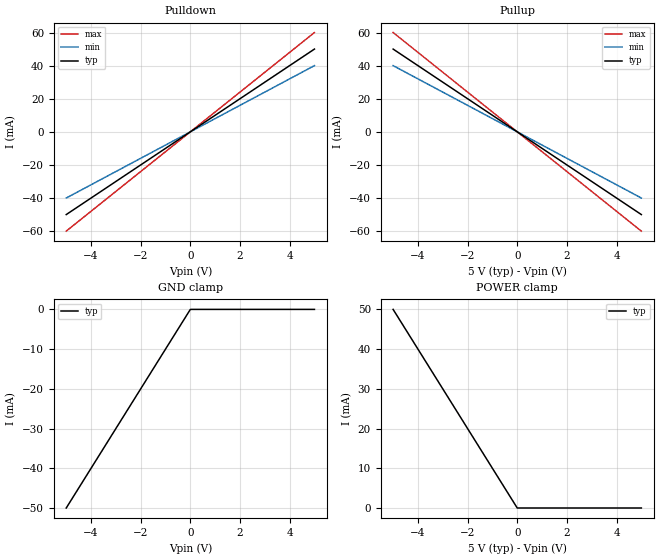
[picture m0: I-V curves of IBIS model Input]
[IBIS Ver]   1.1  |Let's test a comment
[Comment char]  #_char
[File name]   ibis_v1_1.ibs
[File Rev]   1.0  #Let's test a comment
[Date]   26/08/2021
[Source]   This is the
   source for the files
[Notes]   We can have some
   Notes
[Disclaimer]
 * This program source code file is part of KiCad, a free EDA CAD application.
 * Copyright (C) 2017-2021 KiCad Developers, see AUTHORS.txt for contributors.
 * This program is free software; you can redistribute it and/or
 * modify it under the terms of the GNU General Public License
 * as published by the Free Software Foundation; either version 2
 * of the License, or (at your option) any later version.
 * This program is distributed in the hope that it will be useful,
 * but WITHOUT ANY WARRANTY; without even the implied warranty of
 * MERCHANTABILITY or FITNESS FOR A PARTICULAR PURPOSE.  See the
 * GNU General Public License for more details.
 * You should have received a copy of the GNU General Public License
 * along with this program; if not, you may find one here:
 * http://www.gnu.org/licenses/old-licenses/gpl-2.0.html
 * or you may search the http://www.gnu.org website for the version 2 license,
 * or you may write to the Free Software Foundation, Inc.,
 * 51 Franklin Street, Fifth Floor, Boston, MA  02110-1301, USA
[Component]   Virtual
[Manufacturer]  KiCad
[Package]
R_pkg   1m   0.8m   NA
L_pkg   1m   NA   NA
C_pkg   1m   NA   NA
[Pin]   signal_name   model_name   R_pin   L_pin   C_pin
  1   VCC   POWER   1m   0.8m   NA
  2   GND   GND   1m   NA   2m
  3   X   Input   1m   NA   NA
  4   Y   Output   1m   0.8m   2m
# Models and submodels in the file (1): Input (Input)
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[Model]   Input
Model_type   Input
Polarity   Non-Inverting
Enable   Active-High
Vinl = 0.8V
Vinh = 2.0V
C_comp   10.0pF   8.0pF   15.0pF
[Voltage range]   5.0V   4.5V   5.5V
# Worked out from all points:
#   slope of the pulldown table from 0 to 0.75 V, typ, clamps not added: 100 ohm
#   slope of the pullup table from 0 to 0.75 V, typ, clamps not added: 100 ohm
[Pulldown]
#  Voltage   I(typ)   I(min)   I(max)
-5V       -50mA      -40mA      -60mA
0V        0A         0A         0A
5V        50mA       40mA       60mA
[Pullup]
#  Voltage   I(typ)   I(min)   I(max)
-5V       50mA       40mA       60mA
0V        0A         0A         0A
5V        -50mA      -40mA      -60mA
[GND_clamp]
#  Voltage   I(typ)   I(min)   I(max)
-5V       -50mA      NA         NA
0V        0A         NA         NA
5V        0A         NA         NA
[POWER_clamp]
#  Voltage   I(typ)   I(min)   I(max)
-5V       50mA       NA         NA
0V        0A         NA         NA
5V        0A         NA         NA
[Ramp]
# variable   typ   min   max
dV/dt_r   3.0/2n   2.8/3n   NA
dV/dt_f   3.0/2n   2.8/3n   3.2/1n
